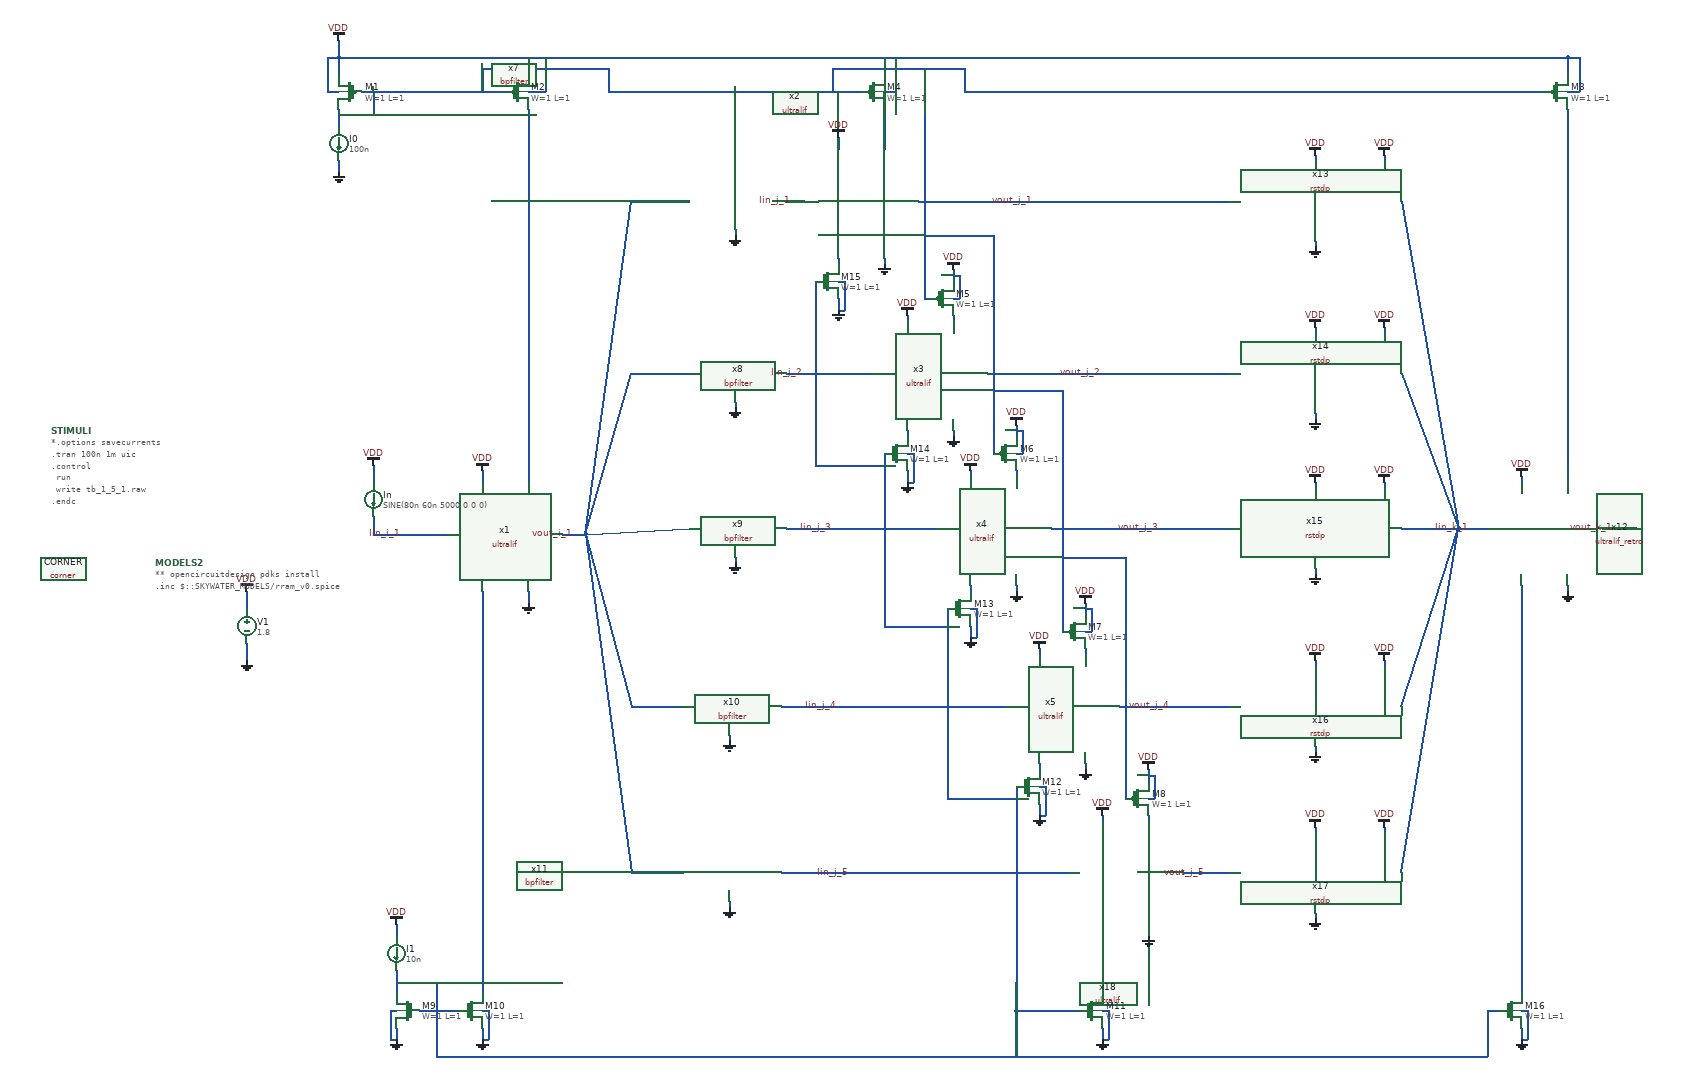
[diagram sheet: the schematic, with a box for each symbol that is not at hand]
v {xschem version=3.4.5 file_version=1.2
}
G {}
K {}
V {}
S {}
E {}
B 2 3790 -140 4590 260 {flags=graph
y1=-0.045
y2=1.9
ypos1=0
ypos2=2
divy=5
subdivy=1
unity=1
x1=-4.9999836e-06
x2=9.5000001e-05
divx=5
subdivx=1
xlabmag=1.0
ylabmag=1.0
node=vout_k_1
color=4
dataset=-1
unitx=1
logx=0
logy=0
}
B 2 2970 -140 3770 260 {flags=graph
y1=-0.0026
y2=1.9
ypos1=0.066870356
ypos2=1.3273691
divy=5
subdivy=1
unity=1
x1=-4.9999836e-06
x2=9.5000001e-05
divx=5
subdivx=1
xlabmag=1.0
ylabmag=1.0


dataset=-1
unitx=1
logx=0
logy=0
color="4 6 7 8 9"
node="vout_j_5
vout_j_4
vout_j_3
vout_j_2
vout_i_1"
digital=0}
B 2 2120 -140 2920 260 {flags=graph
y1=0.00018
y2=0.67
ypos1=0
ypos2=2
divy=5
subdivy=1
unity=1
x1=-4.9999836e-06
x2=9.5000001e-05
divx=5
subdivx=1
xlabmag=1.0
ylabmag=1.0


dataset=-1
unitx=1
logx=0
logy=0
color=4
node=vout_i_1}
B 2 2960 -600 3760 -200 {flags=graph
y1=-0.0045
y2=0.044
ypos1=0
ypos2=2
divy=5
subdivy=1
unity=1
x1=-4.9999836e-06
x2=9.5000001e-05
divx=5
subdivx=1
xlabmag=1.0
ylabmag=1.0


dataset=-1
unitx=1
logx=0
logy=0
color="4 6 7 8 9"
node="Iin_j_1
Iin_j_2
Iin_j_3
Iin_j_4
Iin_j_4"}
B 2 3780 -600 4580 -200 {flags=graph
y1=-0.045
y2=1.9
ypos1=0
ypos2=2
divy=5
subdivy=1
unity=1
x1=-4.9999836e-06
x2=9.5000001e-05
divx=5
subdivx=1
xlabmag=1.0
ylabmag=1.0
node=Iin_k_1
color=4
dataset=-1
unitx=1
logx=0
logy=0
}
B 2 2120 -600 2920 -200 {flags=graph
y1=-0.045
y2=1.9
ypos1=0
ypos2=2
divy=5
subdivy=1
unity=1
x1=-4.9999836e-06
x2=9.5000001e-05
divx=5
subdivx=1
xlabmag=1.0
ylabmag=1.0
node=Iin_i_1
color=4
dataset=-1
unitx=1
logx=0
logy=0
}
N 670 -440 700 -440 {
lab=Iin_j_2}
N 550 -740 580 -740 {
lab=Iin_j_1}
N 780 -170 810 -170 {
lab=Iin_j_3}
N 890 140 930 140 {
lab=Iin_j_4}
N 1000 430 1040 430 {
lab=Iin_j_5}
N 280 -740 380 -740 {
lab=vout_i_1}
N 280 -440 380 -440 {
lab=vout_i_1}
N 280 430 370 430 {
lab=vout_i_1}
N 160 -160 200 -160 {
lab=vout_i_1}
N 200 -160 280 -740 {
lab=vout_i_1}
N 200 -160 280 -440 {
lab=vout_i_1}
N 200 -160 280 430 {
lab=vout_i_1}
N 780 -740 860 -740 {
lab=vout_j_1}
N 900 -440 980 -440 {
lab=vout_j_2}
N 1010 -170 1090 -170 {
lab=vout_j_3}
N 1130 140 1210 140 {
lab=vout_j_4}
N -390 30 -390 60 {
lab=GND}
N -390 -60 -390 -30 {
lab=VDD}
N 20 -270 20 -250 {
lab=VDD}
N 100 -60 100 -40 {
lab=GND}
N -230 -990 -230 -960 {
lab=VDD}
N -230 -1020 -230 -990 {
lab=VDD}
N -230 -900 -230 -870 {
lab=#net1}
N -230 -810 -230 -790 {
lab=GND}
N -250 -930 -230 -930 {
lab=VDD}
N -250 -990 -250 -930 {
lab=VDD}
N -250 -990 -230 -990 {
lab=VDD}
N 640 -850 640 -830 {
lab=VDD}
N 840 -340 840 -330 {
lab=GND}
N -190 -930 -20 -930 {
lab=#net1}
N -230 -890 -170 -890 {
lab=#net1}
N -170 -930 -170 -890 {
lab=#net1}
N 100 -990 100 -960 {
lab=VDD}
N -230 -990 20 -990 {
lab=VDD}
N 20 -990 640 -990 {
lab=VDD}
N 100 -930 130 -930 {
lab=VDD}
N 130 -990 130 -930 {
lab=VDD}
N 860 -930 1410 -930 {
lab=#net1}
N 1100 -990 1910 -990 {
lab=VDD}
N 1910 -990 1910 -960 {
lab=VDD}
N 1910 -930 1930 -930 {
lab=VDD}
N 1930 -990 1930 -930 {
lab=VDD}
N 1910 -990 1930 -990 {
lab=VDD}
N 840 -540 840 -530 {
lab=#net2}
N 1070 40 1070 50 {
lab=#net3}
N 1070 240 1070 250 {
lab=GND}
N 950 -70 950 -60 {
lab=GND}
N 1830 -260 1830 -250 {
lab=VDD}
N 600 -930 680 -930 {
lab=#net1}
N 720 -990 720 -960 {
lab=VDD}
N 720 -900 720 -830 {
lab=#net4}
N 720 -640 720 -630 {
lab=GND}
N 760 -540 760 -530 {
lab=VDD}
N 840 -620 840 -600 {
lab=VDD}
N 790 -570 800 -570 {
lab=#net1}
N 790 -890 790 -570 {
lab=#net1}
N 870 -270 870 -260 {
lab=VDD}
N 840 -570 850 -570 {
lab=VDD}
N 850 -610 850 -570 {
lab=VDD}
N 840 -610 850 -610 {
lab=VDD}
N 950 -350 950 -330 {
lab=VDD}
N 950 -300 960 -300 {
lab=VDD}
N 960 -340 960 -300 {
lab=VDD}
N 950 -340 960 -340 {
lab=VDD}
N 950 -270 950 -260 {
lab=#net5}
N 910 -680 910 -300 {
lab=#net1}
N 790 -680 910 -680 {
lab=#net1}
N 990 40 990 50 {
lab=VDD}
N 1070 -40 1070 -20 {
lab=VDD}
N 1070 10 1080 10 {
lab=VDD}
N 1080 -30 1080 10 {
lab=VDD}
N 1070 -30 1080 -30 {
lab=VDD}
N 1030 -410 1030 10 {
lab=#net1}
N 910 -410 1030 -410 {
lab=#net1}
N 1240 430 1320 430 {
lab=vout_j_5}
N 1180 530 1180 540 {
lab=GND}
N 1180 250 1180 270 {
lab=VDD}
N 1180 300 1190 300 {
lab=VDD}
N 1190 260 1190 300 {
lab=VDD}
N 1180 260 1190 260 {
lab=VDD}
N 1140 -120 1140 300 {
lab=#net1}
N 1180 330 1180 340 {
lab=#net6}
N 1100 330 1100 340 {
lab=VDD}
N 1030 -120 1140 -120 {
lab=#net1}
N 1210 140 1320 140 {
lab=vout_j_4}
N 1090 -170 1320 -170 {
lab=vout_j_3}
N -130 600 -130 640 {
lab=#net7}
N -130 520 -130 540 {
lab=VDD}
N -130 700 -130 720 {
lab=GND}
N -140 670 -130 670 {
lab=GND}
N -140 670 -140 720 {
lab=GND}
N -140 720 -130 720 {
lab=GND}
N 20 -60 20 640 {
lab=#net8}
N 240 -930 600 -930 {
lab=#net1}
N -20 -930 60 -930 {
lab=#net1}
N 20 -970 20 -930 {
lab=#net1}
N 20 -970 240 -970 {
lab=#net1}
N 240 -970 240 -930 {
lab=#net1}
N 100 -900 100 -250 {
lab=#net9}
N 860 -970 860 -930 {
lab=#net1}
N 630 -970 860 -970 {
lab=#net1}
N 630 -970 630 -930 {
lab=#net1}
N 790 -970 790 -890 {
lab=#net1}
N 20 700 20 720 {
lab=GND}
N 30 670 30 720 {
lab=GND}
N 20 720 30 720 {
lab=GND}
N 20 670 30 670 {
lab=GND}
N 1100 700 1100 720 {
lab=GND}
N 1110 670 1110 720 {
lab=GND}
N 1100 720 1110 720 {
lab=GND}
N 1100 670 1110 670 {
lab=GND}
N 1100 530 1100 640 {
lab=#net10}
N 20 750 960 750 {
lab=#net7}
N 960 670 1060 670 {
lab=#net7}
N 990 310 990 330 {
lab=GND}
N 1000 280 1000 330 {
lab=GND}
N 990 330 1000 330 {
lab=GND}
N 990 280 1000 280 {
lab=GND}
N 990 240 990 250 {
lab=#net11}
N 950 280 950 670 {
lab=#net7}
N 950 670 960 670 {
lab=#net7}
N 870 0 870 20 {
lab=GND}
N 880 -30 880 20 {
lab=GND}
N 870 20 880 20 {
lab=GND}
N 870 -30 880 -30 {
lab=GND}
N 870 -70 870 -60 {
lab=#net12}
N 830 -30 830 300 {
lab=#net7}
N 830 300 950 300 {
lab=#net7}
N 760 -270 760 -250 {
lab=GND}
N 770 -300 770 -250 {
lab=GND}
N 760 -250 770 -250 {
lab=GND}
N 760 -300 770 -300 {
lab=GND}
N 760 -340 760 -330 {
lab=#net13}
N 720 -0 830 -0 {
lab=#net7}
N 720 -300 720 -0 {
lab=#net7}
N 640 -570 640 -550 {
lab=GND}
N 650 -600 650 -550 {
lab=GND}
N 640 -550 650 -550 {
lab=GND}
N 640 -600 650 -600 {
lab=GND}
N 640 -640 640 -630 {
lab=#net14}
N 600 -600 600 -280 {
lab=#net7}
N 600 -280 720 -280 {
lab=#net7}
N 540 430 1000 430 {
lab=Iin_j_5}
N 540 140 890 140 {
lab=Iin_j_4}
N 550 -170 780 -170 {
lab=Iin_j_3}
N 550 -440 670 -440 {
lab=Iin_j_2}
N 460 -690 460 -680 {
lab=GND}
N 460 -390 460 -380 {
lab=GND}
N 460 -120 460 -110 {
lab=GND}
N 450 190 450 200 {
lab=GND}
N 450 480 450 490 {
lab=GND}
N 280 140 370 140 {
lab=vout_i_1}
N 200 -160 280 140 {
lab=vout_i_1}
N 950 670 950 750 {
lab=#net7}
N 1770 670 1770 750 {
lab=#net7}
N 1770 670 1790 670 {
lab=#net7}
N 1830 700 1830 720 {
lab=GND}
N 1840 670 1840 720 {
lab=GND}
N 1830 720 1840 720 {
lab=GND}
N 1830 670 1840 670 {
lab=GND}
N 1910 -900 1910 -260 {
lab=#net15}
N 1410 -930 1870 -930 {
lab=#net1}
N 640 -990 1100 -990 {
lab=VDD}
N 1830 -70 1830 640 {
lab=#net16}
N 1470 500 1470 510 {
lab=GND}
N 1470 210 1470 220 {
lab=GND}
N 1470 -100 1470 -90 {
lab=GND}
N 1470 -370 1470 -360 {
lab=GND}
N 1470 -670 1470 -660 {
lab=GND}
N 1470 -820 1470 -810 {
lab=VDD}
N 1470 -520 1470 -510 {
lab=VDD}
N 1470 -250 1470 -240 {
lab=VDD}
N 1470 60 1470 70 {
lab=VDD}
N 1470 350 1470 360 {
lab=VDD}
N 860 -740 1320 -740 {
lab=vout_j_1}
N 980 -440 1320 -440 {
lab=vout_j_2}
N 1620 -170 1770 -170 {
lab=Iin_k_1}
N 1620 -440 1720 -170 {
lab=Iin_k_1}
N 1620 140 1720 -170 {
lab=Iin_k_1}
N 1620 430 1720 -170 {
lab=Iin_k_1}
N 1620 -740 1720 -170 {
lab=Iin_k_1}
N 960 750 1770 750 {
lab=#net7}
N 1970 -170 2030 -170 {
lab=vout_k_1}
N 1910 -70 1910 -60 {
lab=GND}
N 1590 -820 1590 -810 {
lab=VDD}
N 1590 -520 1590 -510 {
lab=VDD}
N 1590 -250 1590 -240 {
lab=VDD}
N 1590 60 1590 70 {
lab=VDD}
N 1590 350 1590 360 {
lab=VDD}
N -120 -160 -40 -160 {
lab=Iin_i_1}
N -170 -160 -120 -160 {
lab=Iin_i_1}
N -170 -190 -170 -160 {
lab=Iin_i_1}
N -170 -280 -170 -250 {
lab=VDD}
N 200 -160 380 -170 {
lab=vout_i_1}
N 720 -930 740 -930 {
lab=VDD}
N 740 -990 740 -930 {
lab=VDD}
N -30 750 20 750 {
lab=#net7}
N -90 670 -20 670 {
lab=#net7}
N -130 620 -60 620 {
lab=#net7}
N -60 620 -60 670 {
lab=#net7}
N -60 750 -30 750 {
lab=#net7}
N -60 670 -60 750 {
lab=#net7}
C {/home/alex/Desktop/EDA/SNN_IPN/Neuron/ultralif/ultralif.sym} 60 -160 0 0 {name=x1}
C {/home/alex/Desktop/EDA/SNN_IPN/Neuron/ultralif/ultralif.sym} 680 -740 0 0 {name=x2}
C {/home/alex/Desktop/EDA/SNN_IPN/Neuron/ultralif/ultralif.sym} 800 -440 0 0 {name=x3}
C {/home/alex/Desktop/EDA/SNN_IPN/Neuron/ultralif/ultralif.sym} 910 -170 0 0 {name=x4}
C {/home/alex/Desktop/EDA/SNN_IPN/Neuron/ultralif/ultralif.sym} 1030 140 0 0 {name=x5}
C {/home/alex/Desktop/EDA/SNN_IPN/Synapse/bpfilter.sym} 380 -680 0 0 {name=x7 C_L=795p C_H=361p}
C {/home/alex/Desktop/EDA/SNN_IPN/Synapse/bpfilter.sym} 380 -380 0 0 {name=x8 C_L=361p C_H=234p}
C {/home/alex/Desktop/EDA/SNN_IPN/Synapse/bpfilter.sym} 380 -110 0 0 {name=x9 C_L=234p C_H=172p}
C {/home/alex/Desktop/EDA/SNN_IPN/Synapse/bpfilter.sym} 370 200 0 0 {name=x10 C_L=172p C_H=137p}
C {/home/alex/Desktop/EDA/SNN_IPN/Synapse/bpfilter.sym} 370 490 0 0 {name=x11 C_L=137p C_H=113p}
C {/home/alex/Desktop/EDA/SNN_IPN/Neuron/ultralif/ultralif_retro.sym} 1870 -170 0 0 {name=x12}
C {/home/alex/Desktop/EDA/SNN_IPN/Synapse/rstdp.sym} 1470 -740 0 0 {name=x13}
C {/home/alex/Desktop/EDA/SNN_IPN/Synapse/rstdp.sym} 1470 -440 0 0 {name=x14}
C {/home/alex/Desktop/EDA/SNN_IPN/Synapse/rstdp.sym} 1470 -170 0 0 {name=x15}
C {/home/alex/Desktop/EDA/SNN_IPN/Synapse/rstdp.sym} 1470 140 0 0 {name=x16}
C {/home/alex/Desktop/EDA/SNN_IPN/Synapse/rstdp.sym} 1470 430 0 0 {name=x17}
C {devices/vsource.sym} -390 0 0 0 {name=V1 value=1.8 savecurrent=false}
C {devices/vdd.sym} -390 -60 0 0 {name=l1 lab=VDD}
C {devices/gnd.sym} -390 60 0 0 {name=l2 lab=GND}
C {devices/gnd.sym} 100 -40 0 0 {name=l4 lab=GND}
C {sky130_fd_pr/pfet_01v8.sym} -210 -930 0 1 {name=M1
L=1
W=1
nf=1
mult=1
ad="'int((nf+1)/2) * W/nf * 0.29'" 
pd="'2*int((nf+1)/2) * (W/nf + 0.29)'"
as="'int((nf+2)/2) * W/nf * 0.29'" 
ps="'2*int((nf+2)/2) * (W/nf + 0.29)'"
nrd="'0.29 / W'" nrs="'0.29 / W'"
sa=0 sb=0 sd=0
model=pfet_01v8
spiceprefix=X
}
C {sky130_fd_pr/pfet_01v8.sym} 80 -930 0 0 {name=M2
L=1
W=1
nf=1
mult=1
ad="'int((nf+1)/2) * W/nf * 0.29'" 
pd="'2*int((nf+1)/2) * (W/nf + 0.29)'"
as="'int((nf+2)/2) * W/nf * 0.29'" 
ps="'2*int((nf+2)/2) * (W/nf + 0.29)'"
nrd="'0.29 / W'" nrs="'0.29 / W'"
sa=0 sb=0 sd=0
model=pfet_01v8
spiceprefix=X
}
C {devices/vdd.sym} -230 -1020 0 0 {name=l5 lab=VDD}
C {devices/isource.sym} -230 -840 0 0 {name=I0 value=100n}
C {devices/gnd.sym} -230 -790 0 0 {name=l6 lab=GND}
C {sky130_fd_pr/pfet_01v8.sym} 700 -930 0 0 {name=M4
L=1
W=1
nf=1
mult=1
ad="'int((nf+1)/2) * W/nf * 0.29'" 
pd="'2*int((nf+1)/2) * (W/nf + 0.29)'"
as="'int((nf+2)/2) * W/nf * 0.29'" 
ps="'2*int((nf+2)/2) * (W/nf + 0.29)'"
nrd="'0.29 / W'" nrs="'0.29 / W'"
sa=0 sb=0 sd=0
model=pfet_01v8
spiceprefix=X
}
C {devices/vdd.sym} 640 -850 0 0 {name=l8 lab=VDD}
C {devices/vdd.sym} 760 -540 3 0 {name=l9 lab=VDD}
C {devices/vdd.sym} 870 -270 0 0 {name=l10 lab=VDD}
C {devices/vdd.sym} 990 40 0 0 {name=l11 lab=VDD}
C {devices/gnd.sym} 1070 250 0 0 {name=l14 lab=GND}
C {devices/gnd.sym} 840 -330 0 0 {name=l16 lab=GND}
C {devices/gnd.sym} 720 -630 0 0 {name=l17 lab=GND}
C {sky130_fd_pr/pfet_01v8.sym} 1890 -930 0 0 {name=M3
L=1
W=1
nf=1
mult=1
ad="'int((nf+1)/2) * W/nf * 0.29'" 
pd="'2*int((nf+1)/2) * (W/nf + 0.29)'"
as="'int((nf+2)/2) * W/nf * 0.29'" 
ps="'2*int((nf+2)/2) * (W/nf + 0.29)'"
nrd="'0.29 / W'" nrs="'0.29 / W'"
sa=0 sb=0 sd=0
model=pfet_01v8
spiceprefix=X
}
C {sky130_fd_pr/pfet_01v8.sym} 820 -570 0 0 {name=M5
L=1
W=1
nf=1
mult=1
ad="'int((nf+1)/2) * W/nf * 0.29'" 
pd="'2*int((nf+1)/2) * (W/nf + 0.29)'"
as="'int((nf+2)/2) * W/nf * 0.29'" 
ps="'2*int((nf+2)/2) * (W/nf + 0.29)'"
nrd="'0.29 / W'" nrs="'0.29 / W'"
sa=0 sb=0 sd=0
model=pfet_01v8
spiceprefix=X
}
C {devices/gnd.sym} 950 -60 0 0 {name=l18 lab=GND}
C {devices/vdd.sym} 1830 -260 0 0 {name=l15 lab=VDD}
C {devices/vdd.sym} 840 -620 0 0 {name=l19 lab=VDD}
C {sky130_fd_pr/pfet_01v8.sym} 930 -300 0 0 {name=M6
L=1
W=1
nf=1
mult=1
ad="'int((nf+1)/2) * W/nf * 0.29'" 
pd="'2*int((nf+1)/2) * (W/nf + 0.29)'"
as="'int((nf+2)/2) * W/nf * 0.29'" 
ps="'2*int((nf+2)/2) * (W/nf + 0.29)'"
nrd="'0.29 / W'" nrs="'0.29 / W'"
sa=0 sb=0 sd=0
model=pfet_01v8
spiceprefix=X
}
C {devices/vdd.sym} 950 -350 0 0 {name=l7 lab=VDD}
C {sky130_fd_pr/pfet_01v8.sym} 1050 10 0 0 {name=M7
L=1
W=1
nf=1
mult=1
ad="'int((nf+1)/2) * W/nf * 0.29'" 
pd="'2*int((nf+1)/2) * (W/nf + 0.29)'"
as="'int((nf+2)/2) * W/nf * 0.29'" 
ps="'2*int((nf+2)/2) * (W/nf + 0.29)'"
nrd="'0.29 / W'" nrs="'0.29 / W'"
sa=0 sb=0 sd=0
model=pfet_01v8
spiceprefix=X
}
C {devices/vdd.sym} 1070 -40 0 0 {name=l20 lab=VDD}
C {/home/alex/Desktop/EDA/SNN_IPN/Neuron/ultralif/ultralif.sym} 1140 430 0 0 {name=x18}
C {devices/gnd.sym} 1180 540 0 0 {name=l21 lab=GND}
C {sky130_fd_pr/pfet_01v8.sym} 1160 300 0 0 {name=M8
L=1
W=1
nf=1
mult=1
ad="'int((nf+1)/2) * W/nf * 0.29'" 
pd="'2*int((nf+1)/2) * (W/nf + 0.29)'"
as="'int((nf+2)/2) * W/nf * 0.29'" 
ps="'2*int((nf+2)/2) * (W/nf + 0.29)'"
nrd="'0.29 / W'" nrs="'0.29 / W'"
sa=0 sb=0 sd=0
model=pfet_01v8
spiceprefix=X
}
C {devices/vdd.sym} 1180 250 0 0 {name=l12 lab=VDD}
C {devices/vdd.sym} 1100 330 0 0 {name=l13 lab=VDD}
C {sky130_fd_pr/nfet_01v8.sym} -110 670 0 1 {name=M9
L=1
W=1
nf=1 
mult=1
ad="'int((nf+1)/2) * W/nf * 0.29'" 
pd="'2*int((nf+1)/2) * (W/nf + 0.29)'"
as="'int((nf+2)/2) * W/nf * 0.29'" 
ps="'2*int((nf+2)/2) * (W/nf + 0.29)'"
nrd="'0.29 / W'" nrs="'0.29 / W'"
sa=0 sb=0 sd=0
model=nfet_01v8
spiceprefix=X
}
C {devices/isource.sym} -130 570 0 0 {name=I1 value=10n}
C {devices/vdd.sym} -130 520 0 0 {name=l22 lab=VDD}
C {devices/gnd.sym} -130 720 0 0 {name=l23 lab=GND}
C {sky130_fd_pr/nfet_01v8.sym} 0 670 0 0 {name=M10
L=1
W=1
nf=1 
mult=1
ad="'int((nf+1)/2) * W/nf * 0.29'" 
pd="'2*int((nf+1)/2) * (W/nf + 0.29)'"
as="'int((nf+2)/2) * W/nf * 0.29'" 
ps="'2*int((nf+2)/2) * (W/nf + 0.29)'"
nrd="'0.29 / W'" nrs="'0.29 / W'"
sa=0 sb=0 sd=0
model=nfet_01v8
spiceprefix=X
}
C {devices/gnd.sym} 20 720 0 1 {name=l24 lab=GND}
C {sky130_fd_pr/nfet_01v8.sym} 1080 670 0 0 {name=M11
L=1
W=1
nf=1 
mult=1
ad="'int((nf+1)/2) * W/nf * 0.29'" 
pd="'2*int((nf+1)/2) * (W/nf + 0.29)'"
as="'int((nf+2)/2) * W/nf * 0.29'" 
ps="'2*int((nf+2)/2) * (W/nf + 0.29)'"
nrd="'0.29 / W'" nrs="'0.29 / W'"
sa=0 sb=0 sd=0
model=nfet_01v8
spiceprefix=X
}
C {devices/gnd.sym} 1100 720 0 1 {name=l25 lab=GND}
C {sky130_fd_pr/nfet_01v8.sym} 970 280 0 0 {name=M12
L=1
W=1
nf=1 
mult=1
ad="'int((nf+1)/2) * W/nf * 0.29'" 
pd="'2*int((nf+1)/2) * (W/nf + 0.29)'"
as="'int((nf+2)/2) * W/nf * 0.29'" 
ps="'2*int((nf+2)/2) * (W/nf + 0.29)'"
nrd="'0.29 / W'" nrs="'0.29 / W'"
sa=0 sb=0 sd=0
model=nfet_01v8
spiceprefix=X
}
C {devices/gnd.sym} 990 330 0 1 {name=l26 lab=GND}
C {sky130_fd_pr/nfet_01v8.sym} 850 -30 0 0 {name=M13
L=1
W=1
nf=1 
mult=1
ad="'int((nf+1)/2) * W/nf * 0.29'" 
pd="'2*int((nf+1)/2) * (W/nf + 0.29)'"
as="'int((nf+2)/2) * W/nf * 0.29'" 
ps="'2*int((nf+2)/2) * (W/nf + 0.29)'"
nrd="'0.29 / W'" nrs="'0.29 / W'"
sa=0 sb=0 sd=0
model=nfet_01v8
spiceprefix=X
}
C {devices/gnd.sym} 870 20 0 1 {name=l27 lab=GND}
C {sky130_fd_pr/nfet_01v8.sym} 740 -300 0 0 {name=M14
L=1
W=1
nf=1 
mult=1
ad="'int((nf+1)/2) * W/nf * 0.29'" 
pd="'2*int((nf+1)/2) * (W/nf + 0.29)'"
as="'int((nf+2)/2) * W/nf * 0.29'" 
ps="'2*int((nf+2)/2) * (W/nf + 0.29)'"
nrd="'0.29 / W'" nrs="'0.29 / W'"
sa=0 sb=0 sd=0
model=nfet_01v8
spiceprefix=X
}
C {devices/gnd.sym} 760 -250 0 1 {name=l28 lab=GND}
C {sky130_fd_pr/nfet_01v8.sym} 620 -600 0 0 {name=M15
L=1
W=1
nf=1 
mult=1
ad="'int((nf+1)/2) * W/nf * 0.29'" 
pd="'2*int((nf+1)/2) * (W/nf + 0.29)'"
as="'int((nf+2)/2) * W/nf * 0.29'" 
ps="'2*int((nf+2)/2) * (W/nf + 0.29)'"
nrd="'0.29 / W'" nrs="'0.29 / W'"
sa=0 sb=0 sd=0
model=nfet_01v8
spiceprefix=X
}
C {devices/gnd.sym} 640 -550 0 1 {name=l29 lab=GND}
C {devices/gnd.sym} 460 -680 0 0 {name=l30 lab=GND}
C {devices/gnd.sym} 460 -380 0 0 {name=l31 lab=GND}
C {devices/gnd.sym} 460 -110 0 0 {name=l32 lab=GND}
C {devices/gnd.sym} 450 200 0 0 {name=l33 lab=GND}
C {devices/gnd.sym} 450 490 0 0 {name=l34 lab=GND}
C {sky130_fd_pr/nfet_01v8.sym} 1810 670 0 0 {name=M16
L=1
W=1
nf=1 
mult=1
ad="'int((nf+1)/2) * W/nf * 0.29'" 
pd="'2*int((nf+1)/2) * (W/nf + 0.29)'"
as="'int((nf+2)/2) * W/nf * 0.29'" 
ps="'2*int((nf+2)/2) * (W/nf + 0.29)'"
nrd="'0.29 / W'" nrs="'0.29 / W'"
sa=0 sb=0 sd=0
model=nfet_01v8
spiceprefix=X
}
C {devices/gnd.sym} 1830 720 0 1 {name=l35 lab=GND}
C {devices/gnd.sym} 1470 510 0 0 {name=l36 lab=GND}
C {devices/gnd.sym} 1470 220 0 0 {name=l37 lab=GND}
C {devices/gnd.sym} 1470 -90 0 0 {name=l38 lab=GND}
C {devices/gnd.sym} 1470 -360 0 0 {name=l39 lab=GND}
C {devices/gnd.sym} 1470 -660 0 0 {name=l40 lab=GND}
C {devices/vdd.sym} 1470 -820 0 0 {name=l41 lab=VDD}
C {devices/vdd.sym} 1470 -520 0 0 {name=l42 lab=VDD}
C {devices/vdd.sym} 1470 -250 0 0 {name=l43 lab=VDD}
C {devices/vdd.sym} 1470 60 0 0 {name=l44 lab=VDD}
C {devices/vdd.sym} 1470 350 0 0 {name=l45 lab=VDD}
C {devices/gnd.sym} 1910 -60 0 0 {name=l46 lab=GND}
C {devices/vdd.sym} 1590 -820 0 0 {name=l47 lab=VDD}
C {devices/vdd.sym} 1590 -520 0 0 {name=l48 lab=VDD}
C {devices/vdd.sym} 1590 -250 0 0 {name=l49 lab=VDD}
C {devices/vdd.sym} 1590 60 0 0 {name=l50 lab=VDD}
C {devices/vdd.sym} 1590 350 0 0 {name=l51 lab=VDD}
C {devices/lab_pin.sym} -120 -160 3 0 {name=p2 sig_type=std_logic lab=Iin_i_1}
C {devices/isource.sym} -170 -220 0 0 {name=In value="SINE(80n 60n 5000 0 0 0)"}
C {devices/vdd.sym} -170 -280 0 0 {name=l52 lab=VDD}
C {sky130_fd_pr/corner.sym} -710 -100 0 0 {name=CORNER only_toplevel=true corner=tt}
C {devices/code_shown.sym} -730 -340 0 0 {name=STIMULI 
only_toplevel=true
place=end
value="
*.options savecurrents
.tran 100n 1m uic
.control
	run
	write tb_1_5_1.raw
.endc
"}
C {devices/code.sym} -550 -110 0 0 {name=MODELS2
only_toplevel=true
format="tcleval( @value )"
value="
** opencircuitdesign pdks install
.inc $::SKYWATER_MODELS/rram_v0.spice
"
spice_ignore=false}
C {devices/launcher.sym} 2210 680 0 0 {name=h5
descr="load waves" 
tclcommand="xschem raw_read $netlist_dir/tb_1_5_1.raw tran"
}
C {devices/lab_pin.sym} 980 -740 3 0 {name=p3 sig_type=std_logic lab=vout_j_1}
C {devices/lab_pin.sym} 1100 -440 3 0 {name=p4 sig_type=std_logic lab=vout_j_2}
C {devices/lab_pin.sym} 1200 -170 3 0 {name=p5 sig_type=std_logic lab=vout_j_3}
C {devices/lab_pin.sym} 1220 140 3 0 {name=p6 sig_type=std_logic lab=vout_j_4}
C {devices/lab_pin.sym} 1280 430 3 0 {name=p7 sig_type=std_logic lab=vout_j_5}
C {devices/lab_pin.sym} 1990 -170 3 0 {name=p8 sig_type=std_logic lab=vout_k_1}
C {devices/lab_pin.sym} 180 -160 3 0 {name=p1 sig_type=std_logic lab=vout_i_1}
C {devices/vdd.sym} 20 -270 0 0 {name=l3 lab=VDD}
C {devices/lab_pin.sym} 560 -740 3 0 {name=p9 sig_type=std_logic lab=Iin_j_1}
C {devices/lab_pin.sym} 580 -440 3 0 {name=p10 sig_type=std_logic lab=Iin_j_2}
C {devices/lab_pin.sym} 630 -170 3 0 {name=p11 sig_type=std_logic lab=Iin_j_3}
C {devices/lab_pin.sym} 640 140 3 0 {name=p12 sig_type=std_logic lab=Iin_j_4}
C {devices/lab_pin.sym} 660 430 3 0 {name=p13 sig_type=std_logic lab=Iin_j_5}
C {devices/lab_pin.sym} 1740 -170 3 0 {name=p14 sig_type=std_logic lab=Iin_k_1}
